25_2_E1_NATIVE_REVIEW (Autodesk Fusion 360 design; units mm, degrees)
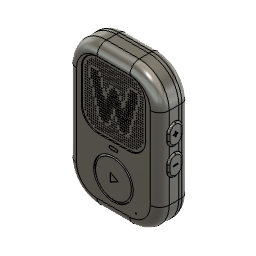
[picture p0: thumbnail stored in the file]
description: Open CASCADE Model
part number: 25_2_E1_FRONT_CONTROL_REVISION
description: Part Number
part number: 11_Speaker_cradle_part
part number: 11_Speaker_cradle
part number: 05_Volume_keys_part
part number: 05_Volume_keys
part number: 06_Status_lens_part
part number: 06_Status_lens
part number: 09_Grille_bond_frame_part
part number: 09_Grille_bond_frame
part number: 12_Rear_alignment_lip_part
base_feature "Base Feature1"
base_feature "Base Feature1"
base_feature "Base Feature1"
base_feature "Base Feature1"
base_feature "Base Feature1"
base_feature "Base Feature1"
base_feature "Base Feature1"
base_feature "Base Feature1"
base_feature "Base Feature1"
base_feature "Base Feature1"
base_feature "Base Feature1"
base_feature "Base Feature1"
base_feature "Base Feature1"
base_feature "Base Feature1"
base_feature "Base Feature1"
base_feature "Base Feature1"
base_feature "Base Feature1"
base_feature "Base Feature1"
base_feature "Base Feature1"
base_feature "Base Feature1"
base_feature "Base Feature1"
base_feature "Base Feature1"
base_feature "Base Feature1"
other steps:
create_component "CreateComponent1"
create_component "CreateComponent1"
create_component "CreateComponent1"
create_component "CreateComponent2"
create_component "CreateComponent1"
create_component "CreateComponent3"
create_component "CreateComponent1"
create_component "CreateComponent4"
create_component "CreateComponent1"
create_component "CreateComponent5"
create_component "CreateComponent1"
create_component "CreateComponent6"
create_component "CreateComponent1"
create_component "CreateComponent7"
create_component "CreateComponent1"
create_component "CreateComponent8"
create_component "CreateComponent1"
create_component "CreateComponent9"
create_component "CreateComponent1"
create_component "CreateComponent10"
create_component "CreateComponent1"
create_component "CreateComponent11"
create_component "CreateComponent1"
create_component "CreateComponent12"
create_component "CreateComponent1"
create_component "CreateComponent13"
create_component "CreateComponent1"
create_component "CreateComponent14"
create_component "CreateComponent1"
create_component "CreateComponent15"
create_component "CreateComponent1"
create_component "CreateComponent16"
create_component "CreateComponent1"
create_component "CreateComponent17"
create_component "CreateComponent1"
create_component "CreateComponent18"
create_component "CreateComponent1"
create_component "CreateComponent19"
create_component "CreateComponent1"
create_component "CreateComponent20"
create_component "CreateComponent1"
create_component "CreateComponent21"
create_component "CreateComponent1"
create_component "CreateComponent22"
create_component "CreateComponent1"
create_component "CreateComponent23"
create_component "CreateComponent1"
